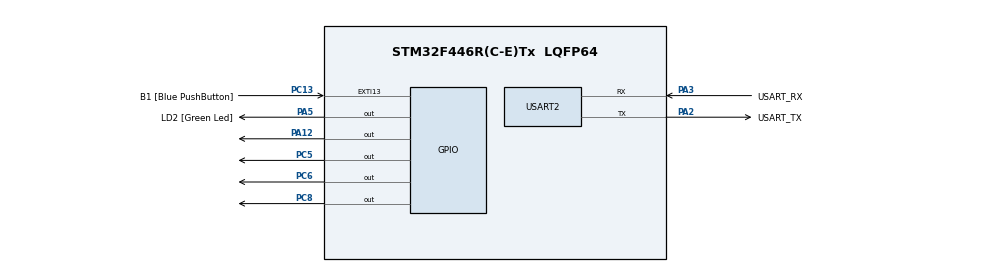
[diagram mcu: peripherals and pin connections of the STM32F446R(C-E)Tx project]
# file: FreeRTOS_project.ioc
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Mcu.Family=STM32F4
Mcu.Name=STM32F446R(C-E)Tx
Mcu.Package=LQFP64
NVIC.PriorityGroup=NVIC_PRIORITYGROUP_4
NVIC.TIM6_DAC_IRQn=true\:0\:0\:false\:false\:true\:false\:true\:true
NVIC.TimeBase=TIM6_DAC_IRQn
NVIC.TimeBaseIP=TIM6
NVIC.USART2_IRQn=true\:6\:0\:true\:false\:true\:true\:true\:true
PA12.Signal=GPIO_Output
PA13.GPIO_Label=TMS
PA13.Mode=Serial_Wire
PA13.Signal=SYS_JTMS-SWDIO
PA14.GPIO_Label=TCK
PA14.Mode=Serial_Wire
PA14.Signal=SYS_JTCK-SWCLK
PA2.GPIO_Label=USART_TX
PA2.Mode=Asynchronous
PA2.Signal=USART2_TX
PA3.GPIO_Label=USART_RX
PA3.Mode=Asynchronous
PA3.Signal=USART2_RX
PA5.GPIO_Label=LD2 [Green Led]
PA5.Signal=GPIO_Output
PB3.GPIO_Label=SWO
PB3.Signal=SYS_JTDO-SWO
PC13.GPIO_Label=B1 [Blue PushButton]
PC13.GPIO_ModeDefaultEXTI=GPIO_MODE_IT_FALLING
PC13.Signal=GPXTI13
PC14-OSC32_IN.Mode=LSE-External-Oscillator
PC14-OSC32_IN.Signal=RCC_OSC32_IN
PC15-OSC32_OUT.Mode=LSE-External-Oscillator
PC15-OSC32_OUT.Signal=RCC_OSC32_OUT
PC5.Signal=GPIO_Output
PC6.Signal=GPIO_Output
PC8.Signal=GPIO_Output
PH0-OSC_IN.Mode=HSE-External-Oscillator
PH0-OSC_IN.Signal=RCC_OSC_IN
PH1-OSC_OUT.Mode=HSE-External-Oscillator
PH1-OSC_OUT.Signal=RCC_OSC_OUT
ProjectManager.HeapSize=0x200
ProjectManager.StackSize=0x400
ProjectManager.TargetToolchain=STM32CubeIDE
RCC.48MHZClocksFreq_Value=84000000
RCC.AHBFreq_Value=84000000
RCC.APB1CLKDivider=RCC_HCLK_DIV2
RCC.APB1Freq_Value=42000000
RCC.APB1TimFreq_Value=84000000
RCC.APB2CLKDivider=RCC_HCLK_DIV2
RCC.APB2Freq_Value=42000000
RCC.APB2TimFreq_Value=84000000
RCC.CortexFreq_Value=84000000
RCC.FLatency-AdvancedSettings=FLASH_LATENCY_2
RCC.HCLKFreq_Value=84000000
RCC.HSE_VALUE=8000000
RCC.HSI_VALUE=16000000
RCC.PLLM=8
RCC.PLLN=84
RCC.SYSCLKFreq_VALUE=84000000
RCC.SYSCLKSource=RCC_SYSCLKSOURCE_PLLCLK
RCC.USBFreq_Value=84000000
RCC.VCOOutputFreq_Value=168000000
RTC.AsynchPrediv=124
RTC.SynchPrediv=139
USART2.VirtualMode=VM_ASYNC
VP_RTC_VS_RTC_Activate.Mode=RTC_Enabled
VP_SYS_VS_tim6.Mode=TIM6
board=NUCLEO-F446RE

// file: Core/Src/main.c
/* USER CODE BEGIN Header */
/**
  ******************************************************************************
  * @file           : main.c
  * @brief          : Main program body
  ******************************************************************************
  * @attention
  *
  * Copyright (c) 2025 STMicroelectronics.
  * All rights reserved.
  *
  * This software is licensed under terms that can be found in the LICENSE file
  * in the root directory of this software component.
  * If no LICENSE file comes with this software, it is provided AS-IS.
  *
  ******************************************************************************
  */
/* USER CODE END Header */
#include "main.h"

RTC_HandleTypeDef hrtc;

UART_HandleTypeDef huart2;

/* USER CODE BEGIN PV */

TaskHandle_t handle_menu_task;
TaskHandle_t handle_led_task;
TaskHandle_t handle_rtc_task;
TaskHandle_t handle_print_task;
TaskHandle_t handle_cmd_task;

QueueHandle_t   Q_print ;
QueueHandle_t   Q_data ;

volatile uint8_t user_data ;

State_t current_state ;

TimerHandle_t handle_led_timer[4];

/* USER CODE END PV */

void SystemClock_Config(void);
static void MX_GPIO_Init(void);
static void MX_USART2_UART_Init(void);
static void MX_RTC_Init(void);
/* USER CODE BEGIN PFP */

void MenuTask(void* parameter);
void PrintTask(void* parameter);
void RtcTask(void* parameter);
void CmdHandleTask(void* parameter);
void LedTask(void* parameter);

void LedEffectCallBackFunc(TimerHandle_t xTimer);

/* USER CODE END PFP */

int main(void)
{

  /* USER CODE BEGIN 1 */
  BaseType_t local_status;

  uint8_t local_counter ;

  /* USER CODE END 1 */

  /* MCU Configuration--------------------------------------------------------*/

  /* Reset of all peripherals, Initializes the Flash interface and the Systick. */
   HAL_Init();

  /* Configure the system clock */
  SystemClock_Config();

  /* Initialize all configured peripherals */
  MX_GPIO_Init();
  MX_USART2_UART_Init();
  MX_RTC_Init();
  /* USER CODE BEGIN 2 */
  /* enable cycle counter feature */

local_status = xTaskCreate(MenuTask, "menu_task", 250, NULL, 2, &handle_menu_task);

configASSERT(local_status == pdPASS);

local_status = xTaskCreate(PrintTask, "print_task", 250, NULL, 2, &handle_print_task);

configASSERT(local_status == pdPASS);

//local_status = xTaskCreate(RtcTask, "rtc_task", 250, NULL, 2, &handle_rtc_task);

//configASSERT(local_status == pdPASS);

local_status = xTaskCreate(LedTask, "led_task", 250, NULL, 2, &handle_led_task);

configASSERT(local_status == pdPASS);

local_status = xTaskCreate(CmdHandleTask, "cmd_task", 250, NULL, 2, &handle_cmd_task);

configASSERT(local_status == pdPASS);

Q_print = xQueueCreate(10 , sizeof(size_t));
configASSERT(Q_print != NULL);

Q_data = xQueueCreate(10 , sizeof(char));
configASSERT(Q_data != NULL);

for(local_counter = 0 ; local_counter < 4 ; local_counter++)
{
handle_led_timer[local_counter] = xTimerCreate("LedTimer" , pdMS_TO_TICKS(500) , pdTRUE , (void*)(local_counter+1) , &LedEffectCallBackFunc);
}

HAL_UART_Receive_IT(&huart2 , (uint8_t*)&user_data , 1);

vTaskStartScheduler();

  /* USER CODE END 2 */

  /* Infinite loop */
  while (1)
  {

  }
}

void SystemClock_Config(void)
{
  RCC_OscInitTypeDef RCC_OscInitStruct = {0};
  RCC_ClkInitTypeDef RCC_ClkInitStruct = {0};

  /** Configure the main internal regulator output voltage
  */
  __HAL_RCC_PWR_CLK_ENABLE();
  __HAL_PWR_VOLTAGESCALING_CONFIG(PWR_REGULATOR_VOLTAGE_SCALE3);

  /** Initializes the RCC Oscillators according to the specified parameters
  * in the RCC_OscInitTypeDef structure.
  */
  RCC_OscInitStruct.OscillatorType = RCC_OSCILLATORTYPE_HSI|RCC_OSCILLATORTYPE_LSI;
  RCC_OscInitStruct.LSEState = RCC_LSE_ON;
  RCC_OscInitStruct.HSIState = RCC_HSI_ON;
  RCC_OscInitStruct.HSICalibrationValue = RCC_HSICALIBRATION_DEFAULT;
  RCC_OscInitStruct.LSIState = RCC_LSI_ON;
  RCC_OscInitStruct.PLL.PLLState = RCC_PLL_ON;
  RCC_OscInitStruct.PLL.PLLSource = RCC_PLLSOURCE_HSI;
  RCC_OscInitStruct.PLL.PLLM = 16;
  RCC_OscInitStruct.PLL.PLLN = 336;
  RCC_OscInitStruct.PLL.PLLP = RCC_PLLP_DIV4;
  RCC_OscInitStruct.PLL.PLLQ = 2;
  RCC_OscInitStruct.PLL.PLLR = 2;
  if (HAL_RCC_OscConfig(&RCC_OscInitStruct) != HAL_OK)
  {
    Error_Handler();
  }

  /** Initializes the CPU, AHB and APB buses clocks
  */
  RCC_ClkInitStruct.ClockType = RCC_CLOCKTYPE_HCLK|RCC_CLOCKTYPE_SYSCLK
                              |RCC_CLOCKTYPE_PCLK1|RCC_CLOCKTYPE_PCLK2;
  RCC_ClkInitStruct.SYSCLKSource = RCC_SYSCLKSOURCE_PLLCLK;
  RCC_ClkInitStruct.AHBCLKDivider = RCC_SYSCLK_DIV1;
  RCC_ClkInitStruct.APB1CLKDivider = RCC_HCLK_DIV2;
  RCC_ClkInitStruct.APB2CLKDivider = RCC_HCLK_DIV1;

  if (HAL_RCC_ClockConfig(&RCC_ClkInitStruct, FLASH_LATENCY_2) != HAL_OK)
  {
    Error_Handler();
  }
}

static void MX_RTC_Init(void)
{

  /** Initialize RTC Only
  */
  hrtc.Instance = RTC;
  hrtc.Init.HourFormat = RTC_HOURFORMAT_24;
  hrtc.Init.AsynchPrediv = 127;
  hrtc.Init.SynchPrediv = 255;
  hrtc.Init.OutPut = RTC_OUTPUT_DISABLE;
  hrtc.Init.OutPutPolarity = RTC_OUTPUT_POLARITY_HIGH;
  hrtc.Init.OutPutType = RTC_OUTPUT_TYPE_OPENDRAIN;
  if (HAL_RTC_Init(&hrtc) != HAL_OK)
  {
    Error_Handler();
  }

}

static void MX_USART2_UART_Init(void)
{

  huart2.Instance = USART2;
  huart2.Init.BaudRate = 115200;
  huart2.Init.WordLength = UART_WORDLENGTH_8B;
  huart2.Init.StopBits = UART_STOPBITS_1;
  huart2.Init.Parity = UART_PARITY_NONE;
  huart2.Init.Mode = UART_MODE_TX_RX;
  huart2.Init.HwFlowCtl = UART_HWCONTROL_NONE;
  huart2.Init.OverSampling = UART_OVERSAMPLING_16;
  if (HAL_UART_Init(&huart2) != HAL_OK)
  {
    Error_Handler();
  }

}

static void MX_GPIO_Init(void)
{
  GPIO_InitTypeDef GPIO_InitStruct = {0};

  /* GPIO Ports Clock Enable */
  __HAL_RCC_GPIOC_CLK_ENABLE();
  __HAL_RCC_GPIOH_CLK_ENABLE();
  __HAL_RCC_GPIOA_CLK_ENABLE();
  __HAL_RCC_GPIOB_CLK_ENABLE();

  /*Configure GPIO pin Output Level */
  HAL_GPIO_WritePin(GPIOA, LD2_Pin|GPIO_PIN_12, GPIO_PIN_RESET);

  /*Configure GPIO pin Output Level */
  HAL_GPIO_WritePin(GPIOC, GPIO_PIN_5|GPIO_PIN_6|GPIO_PIN_8, GPIO_PIN_RESET);

  /*Configure GPIO pin : B1_Pin */
  GPIO_InitStruct.Pin = B1_Pin;
  GPIO_InitStruct.Mode = GPIO_MODE_IT_FALLING;
  GPIO_InitStruct.Pull = GPIO_NOPULL;
  HAL_GPIO_Init(B1_GPIO_Port, &GPIO_InitStruct);

  /*Configure GPIO pins : LD2_Pin PA12 */
  GPIO_InitStruct.Pin = LD2_Pin|GPIO_PIN_12;
  GPIO_InitStruct.Mode = GPIO_MODE_OUTPUT_PP;
  GPIO_InitStruct.Pull = GPIO_NOPULL;
  GPIO_InitStruct.Speed = GPIO_SPEED_FREQ_LOW;
  HAL_GPIO_Init(GPIOA, &GPIO_InitStruct);

  /*Configure GPIO pins : PC5 PC6 PC8 */
  GPIO_InitStruct.Pin = GPIO_PIN_5|GPIO_PIN_6|GPIO_PIN_8;
  GPIO_InitStruct.Mode = GPIO_MODE_OUTPUT_PP;
  GPIO_InitStruct.Pull = GPIO_NOPULL;
  GPIO_InitStruct.Speed = GPIO_SPEED_FREQ_LOW;
  HAL_GPIO_Init(GPIOC, &GPIO_InitStruct);

}

/* USER CODE BEGIN 4 */

void LedEffectCallBackFunc(TimerHandle_t xTimer)
{
  uint8_t local_timer_id ;
  local_timer_id = (uint8_t)pvTimerGetTimerID(xTimer);

  switch(local_timer_id)
  {
    case 1 : LedEffectAction1(); break;
    case 2 : LedEffectAction2(); break;
    case 3 : LedEffectAction3(); break;
    case 4 : LedEffectAction4(); break;
  }
}

void HAL_UART_RxCpltCallback(UART_HandleTypeDef *huart)
{
  if(!xQueueIsQueueFullFromISR(Q_data))
  {
    /*queue is not full */
    xQueueSendFromISR(Q_data ,  (void*)&user_data , NULL);
  }

  else
  {
    /* queue is full */
    if(user_data == '\r')
    {

      xQueueOverwriteFromISR(Q_data , (void*)&user_data , NULL);
    }
    else
    {
      /* Do nothing , ignore the data */
    }
  }

  if(user_data == '\n')
  {
    /* cmd is finished , time to notify the command handling task */
    xTaskNotifyFromISR(handle_cmd_task , 0 , eNoAction , NULL);
  }

  HAL_UART_Receive_IT(&huart2 , (uint8_t*)&user_data , 1);

}

/* USER CODE END 4 */

void HAL_TIM_PeriodElapsedCallback(TIM_HandleTypeDef *htim)
{
  if (htim->Instance == TIM6)
  {
    HAL_IncTick();
  }
}

void Error_Handler(void)
{
  __disable_irq();
  while (1)
  {
  }
}
